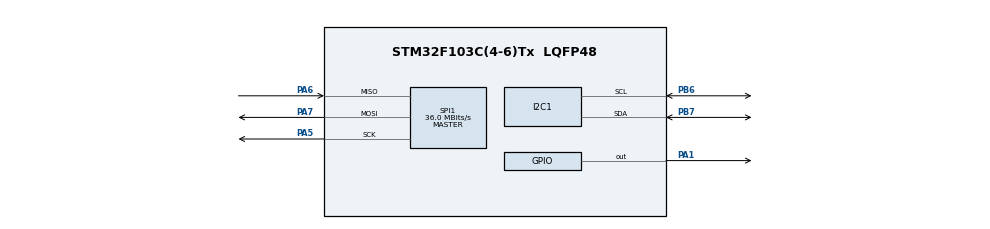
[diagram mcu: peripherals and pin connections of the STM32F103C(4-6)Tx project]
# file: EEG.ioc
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Mcu.Family=STM32F1
<<<<<<< HEAD
Mcu.Name=STM32F103C(8-B)Tx
Mcu.Package=LQFP48
=======
Mcu.Name=STM32F103C(4-6)Tx
Mcu.Package=LQFP48
>>>>>>> cef4edafc774f5850c4bbce70c5b163bffdb6bea
NVIC.PriorityGroup=NVIC_PRIORITYGROUP_4
PA1.Signal=GPIO_Output
PA13.Mode=Serial_Wire
PA13.Signal=SYS_JTMS-SWDIO
PA14.Mode=Serial_Wire
PA14.Signal=SYS_JTCK-SWCLK
PA5.Mode=Full_Duplex_Master
PA5.Signal=SPI1_SCK
PA6.Mode=Full_Duplex_Master
PA6.Signal=SPI1_MISO
PA7.Mode=Full_Duplex_Master
PA7.Signal=SPI1_MOSI
PB6.Mode=I2C
PB6.Signal=I2C1_SCL
PB7.Mode=I2C
PB7.Signal=I2C1_SDA
PD0-OSC_IN.Mode=HSE-External-Oscillator
PD0-OSC_IN.Signal=RCC_OSC_IN
PD1-OSC_OUT.Mode=HSE-External-Oscillator
PD1-OSC_OUT.Signal=RCC_OSC_OUT
ProjectManager.HeapSize=0x200
ProjectManager.StackSize=0x400
ProjectManager.TargetToolchain=STM32CubeIDE
<<<<<<< HEAD
RCC.AHBFreq_Value=72000000
RCC.APB1CLKDivider=RCC_HCLK_DIV2
RCC.APB1Freq_Value=36000000
RCC.APB1TimFreq_Value=72000000
RCC.APB2Freq_Value=72000000
RCC.APB2TimFreq_Value=72000000
RCC.HCLKFreq_Value=72000000
RCC.PLLMUL=RCC_PLL_MUL9
RCC.PLLSourceVirtual=RCC_PLLSOURCE_HSE
RCC.SYSCLKFreq_VALUE=72000000
RCC.SYSCLKSource=RCC_SYSCLKSOURCE_PLLCLK
RCC.USBFreq_Value=72000000
SPI1.BaudRatePrescaler=SPI_BAUDRATEPRESCALER_2
SPI1.CalculateBaudRate=36.0 MBits/s
SPI1.Direction=SPI_DIRECTION_2LINES
SPI1.Mode=SPI_MODE_MASTER
SPI1.VirtualType=VM_MASTER
=======
RCC.APB1Freq_Value=8000000
RCC.APB2Freq_Value=8000000
>>>>>>> cef4edafc774f5850c4bbce70c5b163bffdb6bea
board=custom

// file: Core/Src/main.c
/* USER CODE BEGIN Header */
/**
  ******************************************************************************
  * @file           : main.c
  * @brief          : Main program body
  ******************************************************************************
  * @attention
  *
  * <h2><center>&copy; Copyright (c) 2021 STMicroelectronics.
  * All rights reserved.</center></h2>
  *
  * This software component is licensed by ST under BSD 3-Clause license,
  * the "License"; You may not use this file except in compliance with the
  * License. You may obtain a copy of the License at:
  *                        opensource.org/licenses/BSD-3-Clause
  *
  ******************************************************************************
  */
/* USER CODE END Header */
#include "main.h"

I2C_HandleTypeDef hi2c1;

void SystemClock_Config(void);
static void MX_GPIO_Init(void);
static void MX_I2C1_Init(void);

int main(void)
{

  /* MCU Configuration--------------------------------------------------------*/

  /* Reset of all peripherals, Initializes the Flash interface and the Systick. */
  HAL_Init();

  /* Configure the system clock */
  SystemClock_Config();

  /* Initialize all configured peripherals */
  MX_GPIO_Init();
  MX_I2C1_Init();
  /* USER CODE BEGIN 2 */

  uint16_t DevAddress = (0x16 << 1);

	uint8_t package_size = 3;

	uint8_t data_high[package_size]; // 3 bytes of high data to send
	data_high[0] = 3 << 4;
	data_high[1] = 255;
	data_high[2] = 15 << 4;

	uint8_t data_low[package_size]; // 3 bytes of low data to send
	data_low[0] = 3 << 4;
	data_low[1] = 0;
	data_low[2] = 0;

  /* USER CODE END 2 */

  /* Infinite loop */
  /* USER CODE BEGIN WHILE */
  while (1)
  {
  	HAL_GPIO_TogglePin(GPIOA, GPIO_PIN_1);
		HAL_Delay(100);
		//HAL_I2C_Master_Transmit (&hi2c1, DevAddress, data_high, package_size, HAL_MAX_DELAY);
		HAL_Delay(100);
		//HAL_I2C_Master_Transmit (&hi2c1, DevAddress, data_low, package_size, HAL_MAX_DELAY);

    /* USER CODE END WHILE */

  }
}

void SystemClock_Config(void)
{
  RCC_OscInitTypeDef RCC_OscInitStruct = {0};
  RCC_ClkInitTypeDef RCC_ClkInitStruct = {0};

  /** Initializes the RCC Oscillators according to the specified parameters
  * in the RCC_OscInitTypeDef structure.
  */
  RCC_OscInitStruct.OscillatorType = RCC_OSCILLATORTYPE_HSI;
  RCC_OscInitStruct.HSIState = RCC_HSI_ON;
  RCC_OscInitStruct.HSICalibrationValue = RCC_HSICALIBRATION_DEFAULT;
  RCC_OscInitStruct.PLL.PLLState = RCC_PLL_NONE;
  if (HAL_RCC_OscConfig(&RCC_OscInitStruct) != HAL_OK)
  {
    Error_Handler();
  }
  /** Initializes the CPU, AHB and APB buses clocks
  */
  RCC_ClkInitStruct.ClockType = RCC_CLOCKTYPE_HCLK|RCC_CLOCKTYPE_SYSCLK
                              |RCC_CLOCKTYPE_PCLK1|RCC_CLOCKTYPE_PCLK2;
  RCC_ClkInitStruct.SYSCLKSource = RCC_SYSCLKSOURCE_HSI;
  RCC_ClkInitStruct.AHBCLKDivider = RCC_SYSCLK_DIV1;
  RCC_ClkInitStruct.APB1CLKDivider = RCC_HCLK_DIV1;
  RCC_ClkInitStruct.APB2CLKDivider = RCC_HCLK_DIV1;

  if (HAL_RCC_ClockConfig(&RCC_ClkInitStruct, FLASH_LATENCY_0) != HAL_OK)
  {
    Error_Handler();
  }
}

static void MX_I2C1_Init(void)
{

  hi2c1.Instance = I2C1;
  hi2c1.Init.ClockSpeed = 100000;
  hi2c1.Init.DutyCycle = I2C_DUTYCYCLE_2;
  hi2c1.Init.OwnAddress1 = 0;
  hi2c1.Init.AddressingMode = I2C_ADDRESSINGMODE_7BIT;
  hi2c1.Init.DualAddressMode = I2C_DUALADDRESS_DISABLE;
  hi2c1.Init.OwnAddress2 = 0;
  hi2c1.Init.GeneralCallMode = I2C_GENERALCALL_DISABLE;
  hi2c1.Init.NoStretchMode = I2C_NOSTRETCH_DISABLE;
  if (HAL_I2C_Init(&hi2c1) != HAL_OK)
  {
    Error_Handler();
  }

}

static void MX_GPIO_Init(void)
{
  GPIO_InitTypeDef GPIO_InitStruct = {0};

  /* GPIO Ports Clock Enable */
  __HAL_RCC_GPIOD_CLK_ENABLE();
  __HAL_RCC_GPIOA_CLK_ENABLE();
  __HAL_RCC_GPIOB_CLK_ENABLE();

  /*Configure GPIO pin Output Level */
  HAL_GPIO_WritePin(GPIOA, GPIO_PIN_1, GPIO_PIN_RESET);

  /*Configure GPIO pin : PA1 */
  GPIO_InitStruct.Pin = GPIO_PIN_1;
  GPIO_InitStruct.Mode = GPIO_MODE_OUTPUT_PP;
  GPIO_InitStruct.Pull = GPIO_NOPULL;
  GPIO_InitStruct.Speed = GPIO_SPEED_FREQ_LOW;
  HAL_GPIO_Init(GPIOA, &GPIO_InitStruct);

}

void Error_Handler(void)
{
  __disable_irq();
  while (1)
  {
  }
}

/************************ (C) COPYRIGHT STMicroelectronics *****END OF FILE****/
